VERSION 5.8 ;
BUSBITCHARS "[]" ;
DIVIDERCHAR "/" ;
UNITS
    DATABASE MICRONS 1000 ;
END UNITS

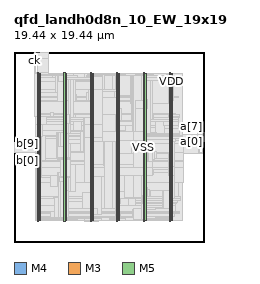
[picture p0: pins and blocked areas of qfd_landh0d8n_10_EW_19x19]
MACRO qfd_landh0d8n_10_EW_19x19
  FOREIGN qfd_landh0d8n_10_EW_19x19 0 0 ;
  CLASS BLOCK ;
  SIZE 19.44 BY 19.44 ;
  PIN a[0]
    DIRECTION INPUT ;
    USE SIGNAL ;
    PORT
      LAYER M4 ;
        RECT  19.356 10.32 19.44 10.344 ;
    END
  END a[0]
  PIN a[1]
    DIRECTION INPUT ;
    USE SIGNAL ;
    PORT
      LAYER M4 ;
        RECT  19.356 10.416 19.44 10.44 ;
    END
  END a[1]
  PIN a[2]
    DIRECTION INPUT ;
    USE SIGNAL ;
    PORT
      LAYER M4 ;
        RECT  19.356 10.512 19.44 10.536 ;
    END
  END a[2]
  PIN a[3]
    DIRECTION INPUT ;
    USE SIGNAL ;
    PORT
      LAYER M4 ;
        RECT  19.356 10.608 19.44 10.632 ;
    END
  END a[3]
  PIN a[4]
    DIRECTION INPUT ;
    USE SIGNAL ;
    PORT
      LAYER M4 ;
        RECT  19.356 10.704 19.44 10.728 ;
    END
  END a[4]
  PIN a[5]
    DIRECTION INPUT ;
    USE SIGNAL ;
    PORT
      LAYER M4 ;
        RECT  19.356 10.8 19.44 10.824 ;
    END
  END a[5]
  PIN a[6]
    DIRECTION INPUT ;
    USE SIGNAL ;
    PORT
      LAYER M4 ;
        RECT  19.356 10.896 19.44 10.92 ;
    END
  END a[6]
  PIN a[7]
    DIRECTION INPUT ;
    USE SIGNAL ;
    PORT
      LAYER M4 ;
        RECT  19.356 10.992 19.44 11.016 ;
    END
  END a[7]
  PIN a[8]
    DIRECTION INPUT ;
    USE SIGNAL ;
    PORT
      LAYER M4 ;
        RECT  19.356 11.088 19.44 11.112 ;
    END
  END a[8]
  PIN a[9]
    DIRECTION INPUT ;
    USE SIGNAL ;
    PORT
      LAYER M4 ;
        RECT  19.356 11.184 19.44 11.208 ;
    END
  END a[9]
  PIN b[0]
    DIRECTION OUTPUT ;
    USE SIGNAL ;
    PORT
      LAYER M4 ;
        RECT  0 9.168 0.084 9.192 ;
    END
  END b[0]
  PIN b[1]
    DIRECTION OUTPUT ;
    USE SIGNAL ;
    PORT
      LAYER M4 ;
        RECT  0 9.264 0.084 9.288 ;
    END
  END b[1]
  PIN b[2]
    DIRECTION OUTPUT ;
    USE SIGNAL ;
    PORT
      LAYER M4 ;
        RECT  0 9.36 0.084 9.384 ;
    END
  END b[2]
  PIN b[3]
    DIRECTION OUTPUT ;
    USE SIGNAL ;
    PORT
      LAYER M4 ;
        RECT  0 9.456 0.084 9.48 ;
    END
  END b[3]
  PIN b[4]
    DIRECTION OUTPUT ;
    USE SIGNAL ;
    PORT
      LAYER M4 ;
        RECT  0 9.552 0.084 9.576 ;
    END
  END b[4]
  PIN b[5]
    DIRECTION OUTPUT ;
    USE SIGNAL ;
    PORT
      LAYER M4 ;
        RECT  0 9.648 0.084 9.672 ;
    END
  END b[5]
  PIN b[6]
    DIRECTION OUTPUT ;
    USE SIGNAL ;
    PORT
      LAYER M4 ;
        RECT  0 9.744 0.084 9.768 ;
    END
  END b[6]
  PIN b[7]
    DIRECTION OUTPUT ;
    USE SIGNAL ;
    PORT
      LAYER M4 ;
        RECT  0 9.84 0.084 9.864 ;
    END
  END b[7]
  PIN b[8]
    DIRECTION OUTPUT ;
    USE SIGNAL ;
    PORT
      LAYER M4 ;
        RECT  0 9.936 0.084 9.96 ;
    END
  END b[8]
  PIN b[9]
    DIRECTION OUTPUT ;
    USE SIGNAL ;
    PORT
      LAYER M4 ;
        RECT  0 10.032 0.084 10.056 ;
    END
  END b[9]
  PIN ck
    DIRECTION INPUT ;
    USE SIGNAL ;
    PORT
      LAYER M3 ;
        RECT  2.124 19.403 2.142 19.44 ;
    END
  END ck
  PIN ck_s
    DIRECTION INPUT ;
    USE SIGNAL ;
    PORT
      LAYER M3 ;
        RECT  2.196 19.403 2.214 19.44 ;
    END
  END ck_s
  PIN en
    DIRECTION INPUT ;
    USE SIGNAL ;
    PORT
      LAYER M3 ;
        RECT  2.268 19.403 2.286 19.44 ;
    END
  END en
  PIN fault
    DIRECTION OUTPUT ;
    USE SIGNAL ;
    PORT
      LAYER M3 ;
        RECT  2.34 19.403 2.358 19.44 ;
    END
  END fault
  PIN k0
    DIRECTION INPUT ;
    USE SIGNAL ;
    PORT
      LAYER M3 ;
        RECT  2.412 19.403 2.43 19.44 ;
    END
  END k0
  PIN k1
    DIRECTION INPUT ;
    USE SIGNAL ;
    PORT
      LAYER M3 ;
        RECT  2.484 19.403 2.502 19.44 ;
    END
  END k1
  PIN k2
    DIRECTION INPUT ;
    USE SIGNAL ;
    PORT
      LAYER M3 ;
        RECT  2.556 19.403 2.574 19.44 ;
    END
  END k2
  PIN k3
    DIRECTION INPUT ;
    USE SIGNAL ;
    PORT
      LAYER M3 ;
        RECT  2.628 19.403 2.646 19.44 ;
    END
  END k3
  PIN rs
    DIRECTION INPUT ;
    USE SIGNAL ;
    PORT
      LAYER M3 ;
        RECT  2.7 19.403 2.718 19.44 ;
    END
  END rs
  PIN tie_hi
    DIRECTION OUTPUT ;
    USE SIGNAL ;
    PORT
      LAYER M3 ;
        RECT  2.772 19.403 2.79 19.44 ;
    END
  END tie_hi
  PIN tie_lo
    DIRECTION OUTPUT ;
    USE SIGNAL ;
    PORT
      LAYER M3 ;
        RECT  2.844 19.403 2.862 19.44 ;
    END
  END tie_lo
  PIN VDD
    DIRECTION INOUT ;
    USE POWER ;
    PORT
      LAYER M5 ;
        RECT  16.092 2.151 16.212 17.289 ;
        RECT  13.392 2.151 13.512 17.289 ;
        RECT  10.692 2.151 10.812 17.289 ;
        RECT  7.992 2.151 8.112 17.289 ;
        RECT  5.292 2.151 5.412 17.289 ;
        RECT  2.592 2.151 2.712 17.289 ;
    END
  END VDD
  PIN VSS
    DIRECTION INOUT ;
    USE GROUND ;
    PORT
      LAYER M5 ;
        RECT  15.9 2.137 16.02 17.303 ;
        RECT  13.2 2.137 13.32 17.303 ;
        RECT  10.5 2.137 10.62 17.303 ;
        RECT  7.8 2.137 7.92 17.303 ;
        RECT  5.1 2.137 5.22 17.303 ;
        RECT  2.4 2.137 2.52 17.303 ;
    END
  END VSS
  # OT_OBS_CLOSED layer=M5 d_um=1.536 added=10
  OBS
    LAYER RVTN ;
     RECT  2.16 2.16 17.28 2.295 ;
     RECT  2.16 2.565 17.28 2.835 ;
     RECT  2.16 3.105 17.28 3.375 ;
     RECT  2.16 3.645 17.28 3.915 ;
     RECT  2.16 4.185 17.28 4.455 ;
     RECT  2.16 4.725 17.28 4.995 ;
     RECT  2.16 5.265 17.28 5.535 ;
     RECT  2.16 5.805 17.28 6.075 ;
     RECT  2.16 6.345 17.28 6.615 ;
     RECT  2.16 6.885 17.28 7.155 ;
     RECT  2.16 7.425 17.28 7.695 ;
     RECT  2.16 7.965 17.28 8.235 ;
     RECT  2.16 8.505 17.28 8.775 ;
     RECT  2.16 9.045 17.28 9.315 ;
     RECT  2.16 9.585 17.28 9.855 ;
     RECT  2.16 10.125 17.28 10.395 ;
     RECT  2.16 10.665 17.28 10.935 ;
     RECT  2.16 11.205 17.28 11.475 ;
     RECT  2.16 11.745 17.28 12.015 ;
     RECT  2.16 12.285 17.28 12.555 ;
     RECT  2.16 12.825 17.28 13.095 ;
     RECT  2.16 13.365 17.28 13.635 ;
     RECT  2.16 13.905 17.28 14.175 ;
     RECT  2.16 14.445 17.28 14.715 ;
     RECT  2.16 14.985 17.28 15.255 ;
     RECT  2.16 15.525 17.28 15.795 ;
     RECT  2.16 16.065 17.28 16.335 ;
     RECT  2.16 16.605 17.28 16.875 ;
     RECT  2.16 17.145 17.28 17.28 ;
    LAYER RVTP ;
     RECT  2.16 2.295 17.28 2.565 ;
     RECT  2.16 2.835 17.28 3.105 ;
     RECT  2.16 3.375 17.28 3.645 ;
     RECT  2.16 3.915 17.28 4.185 ;
     RECT  2.16 4.455 17.28 4.725 ;
     RECT  2.16 4.995 17.28 5.265 ;
     RECT  2.16 5.535 17.28 5.805 ;
     RECT  2.16 6.075 17.28 6.345 ;
     RECT  2.16 6.615 17.28 6.885 ;
     RECT  2.16 7.155 17.28 7.425 ;
     RECT  2.16 7.695 17.28 7.965 ;
     RECT  2.16 8.235 17.28 8.505 ;
     RECT  2.16 8.775 17.28 9.045 ;
     RECT  2.16 9.315 17.28 9.585 ;
     RECT  2.16 9.855 17.28 10.125 ;
     RECT  2.16 10.395 17.28 10.665 ;
     RECT  2.16 10.935 17.28 11.205 ;
     RECT  2.16 11.475 17.28 11.745 ;
     RECT  2.16 12.015 17.28 12.285 ;
     RECT  2.16 12.555 17.28 12.825 ;
     RECT  2.16 13.095 17.28 13.365 ;
     RECT  2.16 13.635 17.28 13.905 ;
     RECT  2.16 14.175 17.28 14.445 ;
     RECT  2.16 14.715 17.28 14.985 ;
     RECT  2.16 15.255 17.28 15.525 ;
     RECT  2.16 15.795 17.28 16.065 ;
     RECT  2.16 16.335 17.28 16.605 ;
     RECT  2.16 16.875 17.28 17.145 ;
    LAYER M1 ;
     RECT  2.16 2.151 17.28 17.289 ;
    LAYER M2 ;
     RECT  2.16 2.151 2.335 17.289 ;
     RECT  2.263 19.386 2.335 19.404 ;
     RECT  2.335 2.151 2.435 17.37 ;
     RECT  2.335 18.81 3.155 19.404 ;
     RECT  3.155 19.386 3.515 19.404 ;
     RECT  2.435 2.151 7.231 17.289 ;
     RECT  7.231 2.106 8.627 17.289 ;
     RECT  8.627 2.151 17.28 17.289 ;
     RECT  17.28 6.12 17.375 6.138 ;
     RECT  17.28 9.09 18.851 10.998 ;
     RECT  18.851 9.09 18.887 9.846 ;
     RECT  18.887 9.09 18.959 9.648 ;
     RECT  18.851 10.71 18.959 10.809 ;
     RECT  18.959 10.71 19.283 10.728 ;
     RECT  18.959 9.09 19.319 9.108 ;
    LAYER M3 ;
     RECT  7.236 2.101 7.254 2.143 ;
     RECT  8.604 2.101 8.622 2.143 ;
     RECT  5.115 2.143 5.205 2.191 ;
     RECT  7.236 2.143 8.622 2.191 ;
     RECT  10.515 2.143 10.605 2.191 ;
     RECT  15.915 2.143 16.005 2.191 ;
     RECT  13.215 2.143 13.305 2.251 ;
     RECT  4.032 2.191 5.205 2.263 ;
     RECT  12.24 2.227 12.258 2.263 ;
     RECT  13.215 2.251 13.59 2.263 ;
     RECT  15.012 2.191 16.005 2.263 ;
     RECT  4.032 2.263 6.138 2.299 ;
     RECT  10.296 2.191 10.605 2.299 ;
     RECT  4.032 2.299 6.462 2.335 ;
     RECT  9.828 2.299 10.605 2.335 ;
     RECT  2.415 2.143 2.505 2.347 ;
     RECT  3.708 2.335 6.462 2.371 ;
     RECT  7.236 2.191 8.946 2.371 ;
     RECT  2.412 2.347 2.505 2.413 ;
     RECT  9.72 2.335 10.605 2.413 ;
     RECT  11.376 2.335 11.394 2.413 ;
     RECT  14.652 2.263 16.005 2.413 ;
     RECT  3.708 2.371 8.946 2.461 ;
     RECT  9.72 2.413 11.394 2.461 ;
     RECT  2.412 2.413 2.697 2.497 ;
     RECT  3.708 2.461 11.394 2.497 ;
     RECT  14.652 2.413 16.197 2.497 ;
     RECT  2.376 2.497 11.394 2.569 ;
     RECT  12.24 2.263 13.59 2.569 ;
     RECT  14.436 2.497 16.197 2.605 ;
     RECT  2.376 2.569 13.59 2.641 ;
     RECT  14.436 2.605 16.47 2.641 ;
     RECT  2.376 2.641 16.47 2.911 ;
     RECT  2.376 2.911 16.938 3.065 ;
     RECT  2.415 3.065 16.938 3.137 ;
     RECT  2.415 3.137 16.542 3.749 ;
     RECT  12.456 3.749 16.542 3.955 ;
     RECT  12.456 3.955 16.578 3.991 ;
     RECT  12.456 3.991 16.686 4.225 ;
     RECT  2.415 3.749 11.718 4.495 ;
     RECT  12.456 4.225 17.082 4.495 ;
     RECT  2.415 4.495 17.082 4.649 ;
     RECT  2.415 4.649 16.866 6.115 ;
     RECT  2.415 6.115 17.37 7.621 ;
     RECT  2.412 7.621 17.37 8.239 ;
     RECT  2.376 8.239 17.37 8.311 ;
     RECT  2.304 8.311 17.37 9.197 ;
     RECT  0.144 9.307 0.162 9.499 ;
     RECT  19.296 9.085 19.314 9.625 ;
     RECT  0.144 9.499 0.234 9.739 ;
     RECT  18.936 9.625 19.314 9.823 ;
     RECT  0.144 9.739 0.342 9.835 ;
     RECT  0.108 9.835 0.342 9.869 ;
     RECT  18.864 9.823 19.314 9.895 ;
     RECT  2.415 9.197 17.37 10.027 ;
     RECT  0.108 9.869 0.126 10.157 ;
     RECT  2.304 10.027 17.37 10.445 ;
     RECT  2.304 10.445 17.118 10.769 ;
     RECT  2.376 10.769 17.118 10.859 ;
     RECT  18.828 9.895 19.314 10.925 ;
     RECT  2.415 10.859 16.902 10.945 ;
     RECT  12.132 10.945 16.902 11.003 ;
     RECT  18.828 10.925 19.278 11.117 ;
     RECT  12.168 11.003 16.902 11.129 ;
     RECT  12.168 11.129 14.526 11.171 ;
     RECT  18.828 11.117 18.846 11.213 ;
     RECT  2.415 10.945 11.394 11.399 ;
     RECT  15.408 11.129 16.902 11.579 ;
     RECT  12.168 11.171 14.454 11.755 ;
     RECT  6.912 11.399 11.394 11.911 ;
     RECT  12.132 11.755 14.454 11.911 ;
     RECT  15.408 11.579 16.83 11.911 ;
     RECT  2.415 11.399 6.138 11.983 ;
     RECT  2.34 11.983 6.138 12.361 ;
     RECT  6.912 11.911 14.454 12.361 ;
     RECT  15.3 11.911 16.83 12.361 ;
     RECT  2.34 12.361 16.83 12.551 ;
     RECT  2.415 12.551 16.83 12.721 ;
     RECT  2.415 12.721 16.902 13.019 ;
     RECT  2.415 13.019 16.506 13.163 ;
     RECT  2.415 13.163 16.197 14.377 ;
     RECT  2.415 14.377 16.218 14.449 ;
     RECT  2.376 14.449 16.326 14.755 ;
     RECT  2.376 14.755 16.866 14.909 ;
     RECT  2.376 14.909 16.326 15.601 ;
     RECT  2.34 15.601 16.326 16.375 ;
     RECT  2.34 16.375 16.434 16.799 ;
     RECT  7.38 16.799 16.197 16.835 ;
     RECT  7.38 16.835 11.61 16.979 ;
     RECT  2.34 16.799 6.498 17.027 ;
     RECT  12.384 16.835 16.197 17.027 ;
     RECT  6.048 17.027 6.498 17.069 ;
     RECT  7.38 16.979 11.466 17.069 ;
     RECT  12.384 17.027 16.005 17.069 ;
     RECT  2.34 17.027 5.205 17.105 ;
     RECT  7.524 17.069 11.394 17.105 ;
     RECT  12.456 17.069 14.274 17.105 ;
     RECT  8.748 17.105 9.774 17.117 ;
     RECT  4.284 17.105 5.205 17.141 ;
     RECT  8.748 17.117 8.766 17.141 ;
     RECT  9.756 17.117 9.774 17.141 ;
     RECT  15.588 17.069 16.005 17.141 ;
     RECT  6.048 17.069 6.066 17.213 ;
     RECT  11.34 17.105 11.358 17.213 ;
     RECT  4.284 17.141 4.302 17.249 ;
     RECT  5.115 17.141 5.205 17.297 ;
     RECT  7.815 17.105 7.905 17.297 ;
     RECT  10.515 17.105 10.605 17.297 ;
     RECT  13.215 17.105 13.305 17.297 ;
     RECT  15.915 17.141 16.005 17.297 ;
     RECT  2.34 17.105 3.51 17.375 ;
     RECT  2.376 17.375 3.51 18.805 ;
     RECT  2.34 18.805 3.51 18.811 ;
     RECT  2.124 18.811 3.51 19.403 ;
     RECT  2.142 19.403 2.196 19.409 ;
     RECT  2.214 19.403 2.268 19.409 ;
     RECT  2.286 19.403 2.34 19.409 ;
     RECT  2.358 19.403 2.412 19.409 ;
     RECT  2.43 19.403 2.484 19.409 ;
     RECT  2.502 19.403 2.556 19.409 ;
     RECT  2.574 19.403 2.628 19.409 ;
     RECT  2.646 19.403 2.7 19.409 ;
     RECT  2.718 19.403 2.772 19.409 ;
     RECT  2.79 19.403 2.844 19.409 ;
     RECT  2.862 19.403 3.51 19.409 ;
     RECT  2.142 19.409 2.196 19.421 ;
     RECT  2.214 19.409 2.268 19.421 ;
     RECT  2.286 19.409 2.34 19.421 ;
     RECT  2.358 19.409 2.412 19.421 ;
     RECT  2.43 19.409 2.484 19.421 ;
     RECT  2.502 19.409 2.556 19.421 ;
     RECT  2.574 19.409 2.628 19.421 ;
     RECT  2.646 19.409 2.7 19.421 ;
     RECT  2.718 19.409 2.772 19.421 ;
     RECT  2.79 19.409 2.844 19.421 ;
    LAYER M4 ;
     RECT  0.084 9.168 0.097 9.192 ;
     RECT  0.06 9.192 0.097 9.264 ;
     RECT  0.084 9.264 0.097 9.288 ;
     RECT  0.06 9.288 0.097 9.36 ;
     RECT  0.084 9.36 0.097 9.384 ;
     RECT  0.06 9.384 0.097 9.456 ;
     RECT  0.084 9.456 0.097 9.48 ;
     RECT  0.06 9.48 0.097 9.552 ;
     RECT  0.084 9.552 0.097 9.576 ;
     RECT  0.06 9.576 0.097 9.648 ;
     RECT  0.084 9.648 0.097 9.672 ;
     RECT  0.06 9.672 0.097 9.744 ;
     RECT  0.084 9.744 0.097 9.768 ;
     RECT  0.06 9.768 0.097 9.84 ;
     RECT  0.084 9.84 0.097 9.864 ;
     RECT  0.06 9.864 0.097 9.936 ;
     RECT  0.084 9.936 0.097 9.96 ;
     RECT  0.06 9.96 0.097 10.032 ;
     RECT  0.084 10.032 0.097 10.056 ;
     RECT  2.053 18.816 2.153 18.84 ;
     RECT  0.097 9.168 2.197 10.152 ;
     RECT  2.156 19.344 2.243 19.368 ;
     RECT  2.053 12.816 2.329 12.84 ;
     RECT  2.401 2.352 2.408 2.376 ;
     RECT  2.401 7.632 2.408 7.656 ;
     RECT  2.197 9.168 2.408 10.344 ;
     RECT  2.329 12 2.408 12.84 ;
     RECT  2.408 2.148 2.512 17.292 ;
     RECT  2.512 2.352 2.704 17.064 ;
     RECT  2.704 6.624 2.819 10.872 ;
     RECT  2.704 3.696 3.017 3.72 ;
     RECT  2.819 8.304 3.197 10.872 ;
     RECT  3.197 8.304 3.233 10.584 ;
     RECT  2.704 12 3.305 12.84 ;
     RECT  2.819 6.624 3.697 6.84 ;
     RECT  3.305 12.816 3.697 12.84 ;
     RECT  2.704 2.352 3.737 2.376 ;
     RECT  2.704 17.04 3.949 17.064 ;
     RECT  3.697 12.816 4.025 13.224 ;
     RECT  3.769 2.496 4.129 3.144 ;
     RECT  4.021 4.512 4.129 4.536 ;
     RECT  2.704 15.264 4.273 15.288 ;
     RECT  3.949 16.8 4.273 17.064 ;
     RECT  3.233 8.544 4.381 10.584 ;
     RECT  3.697 5.712 4.417 6.84 ;
     RECT  4.273 15.264 4.417 17.064 ;
     RECT  4.381 8.544 4.453 11.16 ;
     RECT  4.453 8.496 4.525 11.16 ;
     RECT  4.129 2.496 4.561 4.536 ;
     RECT  4.417 5.712 4.561 7.128 ;
     RECT  4.561 2.496 4.777 7.128 ;
     RECT  4.525 8.4 4.777 11.16 ;
     RECT  4.777 2.496 5.108 11.16 ;
     RECT  4.025 12.816 5.108 12.84 ;
     RECT  4.417 14.4 5.108 17.064 ;
     RECT  5.108 2.148 5.212 17.292 ;
     RECT  5.212 2.418 5.404 17.022 ;
     RECT  5.404 2.496 5.555 4.152 ;
     RECT  5.404 5.136 5.573 16.584 ;
     RECT  5.573 5.136 5.747 10.056 ;
     RECT  5.747 5.136 5.789 8.184 ;
     RECT  5.573 11.136 5.789 16.584 ;
     RECT  5.789 12.72 6.041 16.584 ;
     RECT  5.789 5.136 6.293 7.896 ;
     RECT  6.041 12.72 6.293 13.032 ;
     RECT  6.041 14.4 6.293 16.584 ;
     RECT  6.293 14.4 6.329 15.432 ;
     RECT  6.329 14.496 6.401 15.096 ;
     RECT  5.747 9.264 6.757 10.056 ;
     RECT  5.789 11.136 6.757 11.304 ;
     RECT  5.555 3.408 7.045 4.152 ;
     RECT  6.757 9.264 7.081 11.304 ;
     RECT  6.293 12.72 7.081 12.744 ;
     RECT  6.293 6.096 7.225 7.896 ;
     RECT  7.081 9.264 7.225 12.744 ;
     RECT  6.401 14.496 7.369 14.808 ;
     RECT  7.369 14.496 7.657 15.336 ;
     RECT  7.045 3.408 7.808 5.016 ;
     RECT  7.225 6.096 7.808 12.744 ;
     RECT  7.657 14.496 7.808 15.576 ;
     RECT  6.293 16.56 7.808 16.584 ;
     RECT  7.808 2.148 7.912 17.292 ;
     RECT  7.912 2.418 8.104 17.022 ;
     RECT  8.104 12.048 8.849 12.072 ;
     RECT  8.104 2.832 8.921 6.696 ;
     RECT  8.104 13.056 9.097 16.92 ;
     RECT  8.104 7.968 9.133 11.064 ;
     RECT  8.921 3.408 9.241 6.696 ;
     RECT  9.133 7.872 9.241 11.064 ;
     RECT  9.097 13.056 9.241 17.112 ;
     RECT  9.241 12.48 9.245 17.112 ;
     RECT  9.241 3.408 10.033 11.064 ;
     RECT  9.245 12.48 10.033 17.016 ;
     RECT  10.033 3.408 10.357 17.016 ;
     RECT  10.357 2.88 10.393 17.016 ;
     RECT  10.393 2.544 10.508 17.016 ;
     RECT  10.508 2.148 10.612 17.292 ;
     RECT  10.612 2.418 10.804 17.064 ;
     RECT  10.804 2.544 10.865 2.904 ;
     RECT  10.804 3.984 10.901 6.84 ;
     RECT  10.804 12.432 11.009 13.704 ;
     RECT  10.804 15.024 11.869 17.064 ;
     RECT  10.804 7.92 11.989 9.528 ;
     RECT  10.804 10.704 11.989 10.92 ;
     RECT  11.009 12.432 12.013 13.08 ;
     RECT  11.869 14.208 12.013 17.064 ;
     RECT  10.865 2.544 12.121 2.568 ;
     RECT  11.989 7.92 12.121 10.92 ;
     RECT  12.013 12.432 12.121 17.064 ;
     RECT  12.121 2.544 12.193 3.336 ;
     RECT  12.193 2.544 12.229 3.384 ;
     RECT  10.901 4.512 12.229 6.84 ;
     RECT  12.121 7.92 12.229 17.064 ;
     RECT  12.229 2.256 13.093 3.384 ;
     RECT  12.229 4.512 13.093 17.064 ;
     RECT  13.093 2.256 13.208 17.064 ;
     RECT  13.208 2.148 13.312 17.292 ;
     RECT  13.312 2.256 13.504 17.022 ;
     RECT  13.504 2.256 13.601 2.376 ;
     RECT  13.504 3.36 13.601 5.592 ;
     RECT  13.601 4.656 13.709 5.592 ;
     RECT  13.504 6.816 13.715 9.816 ;
     RECT  13.709 4.656 13.817 5.4 ;
     RECT  13.504 11.136 13.925 16.536 ;
     RECT  13.817 4.656 13.997 5.304 ;
     RECT  13.715 6.816 14.147 9.288 ;
     RECT  13.925 12.528 14.177 16.536 ;
     RECT  14.147 6.864 14.285 7.416 ;
     RECT  14.177 12.528 14.285 13.08 ;
     RECT  14.147 8.448 14.393 9.288 ;
     RECT  13.601 3.36 14.501 3.48 ;
     RECT  13.925 11.136 14.537 11.16 ;
     RECT  14.393 8.496 14.573 9.288 ;
     RECT  14.501 3.456 15.181 3.48 ;
     RECT  13.997 4.656 15.181 5.256 ;
     RECT  15.181 3.456 15.289 5.256 ;
     RECT  14.285 7.152 15.781 7.416 ;
     RECT  14.573 8.496 15.781 9.096 ;
     RECT  14.285 13.056 15.829 13.08 ;
     RECT  13.601 2.352 15.908 2.376 ;
     RECT  15.289 3.456 15.908 5.304 ;
     RECT  15.781 6.816 15.908 9.096 ;
     RECT  14.929 10.08 15.908 10.104 ;
     RECT  15.829 12.768 15.908 13.08 ;
     RECT  14.177 14.208 15.908 16.536 ;
     RECT  15.908 2.148 16.012 17.292 ;
     RECT  16.012 2.418 16.204 17.022 ;
     RECT  16.204 7.152 16.337 7.752 ;
     RECT  16.337 7.728 16.355 7.752 ;
     RECT  16.204 9.12 16.355 9.144 ;
     RECT  16.204 4.512 16.451 4.536 ;
     RECT  16.204 10.272 16.489 10.632 ;
     RECT  16.204 12.768 16.913 12.792 ;
     RECT  16.489 10.416 18.817 10.632 ;
     RECT  18.817 10.32 19.356 10.344 ;
     RECT  18.817 10.344 19.404 10.416 ;
     RECT  18.817 10.416 19.356 10.44 ;
     RECT  18.817 10.44 19.404 10.512 ;
     RECT  18.817 10.512 19.356 10.536 ;
     RECT  18.817 10.536 19.404 10.608 ;
     RECT  18.817 10.608 19.356 10.632 ;
     RECT  18.817 10.632 19.404 10.704 ;
     RECT  18.817 10.704 19.356 10.728 ;
     RECT  18.817 10.728 19.404 10.8 ;
     RECT  18.817 10.8 19.356 10.824 ;
     RECT  18.817 10.824 19.404 10.896 ;
     RECT  18.817 10.896 19.356 10.92 ;
     RECT  18.817 10.92 19.404 10.992 ;
     RECT  18.817 10.992 19.356 11.016 ;
     RECT  18.817 11.016 19.404 11.088 ;
     RECT  18.817 11.088 19.356 11.112 ;
     RECT  18.817 11.112 19.404 11.184 ;
     RECT  18.817 11.184 19.356 11.208 ;
    LAYER M5 ;
     RECT  2.4 2.137 2.52 2.151 ;
     RECT  5.1 2.137 5.22 2.151 ;
     RECT  7.8 2.137 7.92 2.151 ;
     RECT  10.5 2.137 10.62 2.151 ;
     RECT  13.2 2.137 13.32 2.151 ;
     RECT  15.9 2.137 16.02 2.151 ;
     RECT  5.1 2.151 5.412 2.485 ;
     RECT  7.8 2.151 8.112 2.821 ;
     RECT  7.8 2.821 8.568 3.443 ;
     RECT  13.2 2.151 13.512 3.925 ;
     RECT  10.5 2.151 10.812 4.501 ;
     RECT  15.9 2.151 16.212 4.501 ;
     RECT  13.104 3.925 13.512 4.787 ;
     RECT  10.5 4.501 11.352 5.171 ;
     RECT  5.1 2.485 5.544 5.315 ;
     RECT  5.1 5.315 5.412 6.229 ;
     RECT  2.4 2.151 2.712 6.613 ;
     RECT  4.656 6.229 5.412 6.613 ;
     RECT  4.656 6.613 5.736 6.659 ;
     RECT  10.5 5.171 11.304 6.805 ;
     RECT  13.2 4.787 13.512 6.805 ;
     RECT  15.9 4.501 16.44 6.805 ;
     RECT  10.5 6.805 14.136 7.619 ;
     RECT  2.4 6.613 2.808 7.667 ;
     RECT  15.792 6.805 16.44 7.763 ;
     RECT  10.5 7.619 12.216 7.955 ;
     RECT  13.2 7.619 14.136 8.195 ;
     RECT  5.1 6.659 5.736 8.485 ;
     RECT  4.464 8.485 5.736 8.579 ;
     RECT  4.464 8.579 5.688 8.675 ;
     RECT  12.192 7.955 12.216 9.061 ;
     RECT  4.464 8.675 5.412 9.779 ;
     RECT  13.2 8.195 13.704 9.827 ;
     RECT  7.8 3.443 8.112 10.261 ;
     RECT  15.9 7.763 16.44 10.307 ;
     RECT  2.4 7.667 2.712 10.309 ;
     RECT  12 9.061 12.216 10.357 ;
     RECT  13.2 9.827 13.512 10.357 ;
     RECT  12 10.357 13.512 10.403 ;
     RECT  7.8 10.261 9.048 10.741 ;
     RECT  2.208 10.309 2.712 10.837 ;
     RECT  5.1 9.779 5.412 11.125 ;
     RECT  12.192 10.403 13.512 11.267 ;
     RECT  10.5 7.955 10.812 11.269 ;
     RECT  2.208 10.837 2.904 12.035 ;
     RECT  7.248 10.741 9.048 12.035 ;
     RECT  5.1 11.125 5.544 12.133 ;
     RECT  2.208 12.035 2.712 12.805 ;
     RECT  5.1 12.133 5.688 13.091 ;
     RECT  10.368 11.269 10.812 13.091 ;
     RECT  12.48 11.267 13.512 13.621 ;
     RECT  15.9 10.307 16.212 14.197 ;
     RECT  5.1 13.091 5.544 14.435 ;
     RECT  12.48 13.621 13.704 14.435 ;
     RECT  13.2 14.435 13.704 14.627 ;
     RECT  10.5 13.091 10.812 14.773 ;
     RECT  10.272 14.773 10.812 15.443 ;
     RECT  7.8 12.035 9.048 15.635 ;
     RECT  15.792 14.197 16.212 16.019 ;
     RECT  5.1 14.435 5.412 16.405 ;
     RECT  4.512 16.405 5.412 17.075 ;
     RECT  2.064 12.805 2.712 17.289 ;
     RECT  5.1 17.075 5.412 17.289 ;
     RECT  7.8 15.635 8.112 17.289 ;
     RECT  10.5 15.443 10.812 17.289 ;
     RECT  13.2 14.627 13.512 17.289 ;
     RECT  15.9 16.019 16.212 17.289 ;
     RECT  2.064 17.289 2.52 17.303 ;
     RECT  5.1 17.289 5.22 17.303 ;
     RECT  7.8 17.289 7.92 17.303 ;
     RECT  10.5 17.289 10.62 17.303 ;
     RECT  13.2 17.289 13.32 17.303 ;
     RECT  15.9 17.289 16.02 17.303 ;
     RECT  2.064 17.303 2.232 18.851 ;
     RECT  2.208 18.851 2.232 19.379 ;
     RECT  5.412 5.315 5.544 6.613 ;
     RECT  12.216 7.619 13.2 10.357 ;
     RECT  10.812 7.955 12.192 9.061 ;
     RECT  10.812 9.061 12 10.403 ;
     RECT  9.048 10.261 10.5 11.269 ;
     RECT  10.812 10.403 12.192 11.267 ;
     RECT  9.048 11.269 10.368 13.091 ;
     RECT  9.048 13.091 10.5 14.773 ;
     RECT  9.048 14.773 10.272 15.443 ;
     RECT  9.048 15.443 10.5 15.635 ;
  END
END qfd_landh0d8n_10_EW_19x19
END LIBRARY
